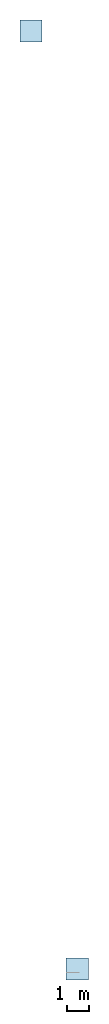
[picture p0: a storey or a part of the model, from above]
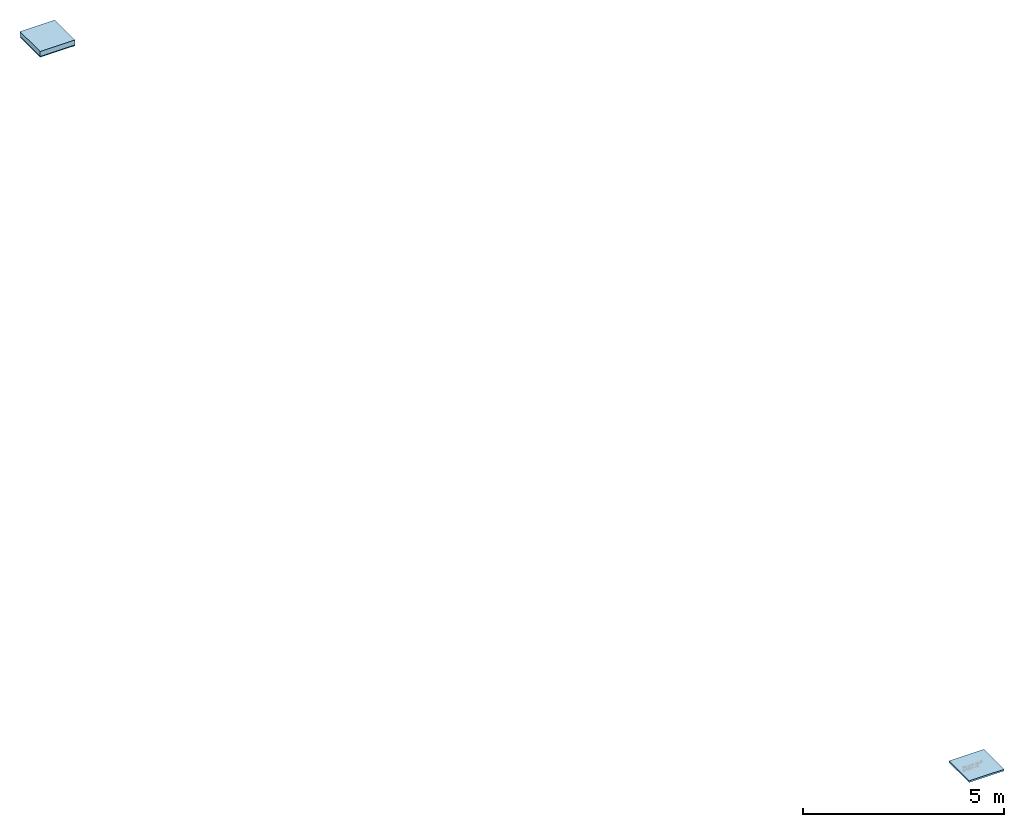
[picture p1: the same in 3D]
Properties of the parts of a building model (IFC2X3)

# File
Description: ViewDefinition [CoordinationView_V2.0], RevitIdentifiers [VersionGUID: 578dc951-38f8-42b4-9d55-27c226baf1a5, NumberOfSaves: 2], CoordinateReference [CoordinateBase: Gemeinsam genutzte Koordinaten]
File name: 2018_01
Time: 2023-07-05T09:27:00+01:00
Written by: ODA SDAI 23.12
Made in: Autodesk Revit 24.0.5.432 (DEU) - IFC 24.0.5.432

# IfcProject, 2018_01
Phase: Projekt Status

# IfcSite, Default
RefLatitude: 48, 8, 15, 359802; RefLongitude: 11, 34, 47, 783432; RefElevation: 0 m

# IfcBuildingElementProxy: Modelltext:075mm Arial, Modelltext:075mm Arial:2510299
In: Default
Pset_BuildingElementProxyCommon - Reference: 075mm Arial; sets with these values: 2
Pset_ProvisionForVoid - Shape: Undefined; Width: 0.025 m; Height: 0.0294306 m; Depth: 0.0294306 m

# IfcElementAssembly: Dächer Baugruppe:fbimSg_Roof_bc_WOD_vis_at_NTR_natuREbuilt_FD-HS-HLÜ-GRÜN-VS_GK3_81cm, Dächer Baugruppe:fbimSg_Roof_bc_WOD_vis_at_NTR_natuREbuilt_FD-HS-HLÜ-GRÜN-VS_GK3_81cm:2510327
In: Default
PredefinedType: USERDEFINED; Material: fbim_12400515_AT_025_Vollholz_Bretter_Fichte 0.024 m, fbim_14100500_at_NTR_Zellulose-Einblasdaemmung 0.38 m, fbim_12400515_AT_025_Vollholz_Bretter_Fichte 0.024 m
Pset_QuantityTakeOff - Reference: fbimSg_Roof_bc_WOD_vis_at_NTR_natuREbuilt_FD-HS-HLÜ-GRÜN-VS_GK3_81cm

# IfcRoof: Basisdach:fbimSg_Roof_dp_DRW_vis_at_NTR_natuREbuilt_DRh_GK3_u_1,25cm, Basisdach:fbimSg_Roof_dp_DRW_vis_at_NTR_natuREbuilt_DRh_GK3_u_1,25cm:2510320
In: Default
Material: fbim_16101505_AT_Gipsfaserplatte 0.0125 m, fbim_14153005_AT_001_KlebeArmierspachtel_min 0.001 m
Pset_QuantityTakeOff - Reference: fbimSg_Roof_dp_DRW_vis_at_NTR_natuREbuilt_DRh_GK3_u_1,25cm
Pset_RoofCommon - IsExternal: yes; Reference: fbimSg_Roof_dp_DRW_vis_at_NTR_natuREbuilt_DRh_GK3_u_1,25cm; ProjectedArea: 1 m2; TotalArea: 1 m2

# IfcRoof: Basisdach:fbimSg_Roof_dp_INS_vis_at_NTR_natuREbuilt_DRh_GK3_o_12cm, Basisdach:fbimSg_Roof_dp_INS_vis_at_NTR_natuREbuilt_DRh_GK3_o_12cm:2510311
In: Default
Material: fbim_20252030_AT_Begruenung_extensiv 0.08 m, fbim_10200515_AT_001_Schutzvlies 0.0032 m, fbim_14052005_AT_EPDM_Abdichtungsbahn 0.0018 m, fbim_10200515_AT_001_Schutzvlies 0.0009 m, fbim_12400515_AT_025_Vollholz_Bretter_Fichte 0.024 m, fbim_14100590_AT_001_Luftschicht 0.1 m, fbim_12400520_AT_001_Vollholz_Lattung_Fichte 0.1 m
Pset_QuantityTakeOff - Reference: fbimSg_Roof_dp_INS_vis_at_NTR_natuREbuilt_DRh_GK3_o_12cm
Pset_RoofCommon - IsExternal: yes; Reference: fbimSg_Roof_dp_INS_vis_at_NTR_natuREbuilt_DRh_GK3_o_12cm; ProjectedArea: 1 m2; TotalArea: 1 m2

# IfcRoof: Basisdach:fbimSg_Roof_sb_WOD_vis_at_NTR_natuREbuilt_DRh_GK3_k_38cm, Basisdach:fbimSg_Roof_sb_WOD_vis_at_NTR_natuREbuilt_DRh_GK3_k_38cm:2510302
In: Default
Pset_QuantityTakeOff - Reference: fbimSg_Roof_sb_WOD_vis_at_NTR_natuREbuilt_DRh_GK3_k_38cm
Pset_RoofCommon - Reference: fbimSg_Roof_sb_WOD_vis_at_NTR_natuREbuilt_DRh_GK3_k_38cm; IsExternal: yes; ProjectedArea: 1 m2; TotalArea: 1 m2

# IfcSlab: Basisdach:fbimSg_Roof_dp_DRW_vis_at_NTR_natuREbuilt_DRh_GK3_u_1,25cm, Basisdach:fbimSg_Roof_dp_DRW_vis_at_NTR_natuREbuilt_DRh_GK3_u_1,25cm:2510320
In: Default
Type - PredefinedType: ROOF
Type - Pset_SlabCommon - IsExternal: yes
Material: fbim_16101505_AT_Gipsfaserplatte 0.0125 m, fbim_14153005_AT_001_KlebeArmierspachtel_min 0.001 m
Pset_QuantityTakeOff - Reference: fbimSg_Roof_dp_DRW_vis_at_NTR_natuREbuilt_DRh_GK3_u_1,25cm; sets with these values: 2
Pset_SlabCommon - PitchAngle: 0 deg; Reference: fbimSg_Roof_dp_DRW_vis_at_NTR_natuREbuilt_DRh_GK3_u_1,25cm

# IfcSlab: Basisdach:fbimSg_Roof_dp_INS_vis_at_NTR_natuREbuilt_DRh_GK3_o_12cm, Basisdach:fbimSg_Roof_dp_INS_vis_at_NTR_natuREbuilt_DRh_GK3_o_12cm:2510311:1
In: Default
Type - PredefinedType: ROOF
Type - Pset_SlabCommon - IsExternal: yes
Pset_QuantityTakeOff - Reference: fbimSg_Roof_dp_INS_vis_at_NTR_natuREbuilt_DRh_GK3_o_12cm; sets with these values: 2
Pset_SlabCommon - PitchAngle: 0 deg; Reference: fbimSg_Roof_dp_INS_vis_at_NTR_natuREbuilt_DRh_GK3_o_12cm

# IfcSlab: Basisdach:fbimSg_Roof_sb_WOD_vis_at_NTR_natuREbuilt_DRh_GK3_k_38cm, Basisdach:fbimSg_Roof_sb_WOD_vis_at_NTR_natuREbuilt_DRh_GK3_k_38cm:2510302
In: Default
Type - PredefinedType: ROOF
Type - Pset_SlabCommon - IsExternal: yes
Material: fbim_12400515_AT_025_Vollholz_Bretter_Fichte 0.024 m, fbim_14100500_at_NTR_Zellulose-Einblasdaemmung 0.38 m, fbim_12400515_AT_025_Vollholz_Bretter_Fichte 0.024 m
Pset_QuantityTakeOff - Reference: fbimSg_Roof_sb_WOD_vis_at_NTR_natuREbuilt_DRh_GK3_k_38cm; sets with these values: 2
Pset_SlabCommon - Reference: fbimSg_Roof_sb_WOD_vis_at_NTR_natuREbuilt_DRh_GK3_k_38cm; PitchAngle: 0 deg
